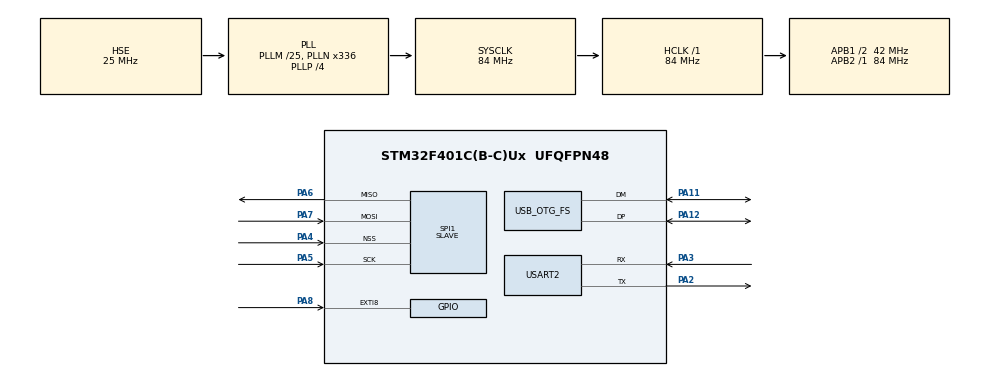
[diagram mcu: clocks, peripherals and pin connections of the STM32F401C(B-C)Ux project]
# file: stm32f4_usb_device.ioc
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Dma.Request0=SPI1_RX
Dma.Request1=SPI1_TX
Dma.Request2=USART2_RX
Dma.Request3=USART2_TX
Dma.SPI1_RX.0.Direction=DMA_PERIPH_TO_MEMORY
Dma.SPI1_RX.0.FIFOMode=DMA_FIFOMODE_DISABLE
Dma.SPI1_RX.0.Instance=DMA2_Stream0
Dma.SPI1_RX.0.MemDataAlignment=DMA_MDATAALIGN_BYTE
Dma.SPI1_RX.0.MemInc=DMA_MINC_ENABLE
Dma.SPI1_RX.0.Mode=DMA_NORMAL
Dma.SPI1_RX.0.PeriphDataAlignment=DMA_PDATAALIGN_BYTE
Dma.SPI1_RX.0.PeriphInc=DMA_PINC_DISABLE
Dma.SPI1_RX.0.Priority=DMA_PRIORITY_LOW
Dma.SPI1_TX.1.Direction=DMA_MEMORY_TO_PERIPH
Dma.SPI1_TX.1.FIFOMode=DMA_FIFOMODE_DISABLE
Dma.SPI1_TX.1.Instance=DMA2_Stream3
Dma.SPI1_TX.1.MemDataAlignment=DMA_MDATAALIGN_BYTE
Dma.SPI1_TX.1.MemInc=DMA_MINC_ENABLE
Dma.SPI1_TX.1.Mode=DMA_NORMAL
Dma.SPI1_TX.1.PeriphDataAlignment=DMA_PDATAALIGN_BYTE
Dma.SPI1_TX.1.PeriphInc=DMA_PINC_DISABLE
Dma.SPI1_TX.1.Priority=DMA_PRIORITY_LOW
Dma.USART2_RX.2.Direction=DMA_PERIPH_TO_MEMORY
Dma.USART2_RX.2.FIFOMode=DMA_FIFOMODE_DISABLE
Dma.USART2_RX.2.Instance=DMA1_Stream5
Dma.USART2_RX.2.MemDataAlignment=DMA_MDATAALIGN_BYTE
Dma.USART2_RX.2.MemInc=DMA_MINC_ENABLE
Dma.USART2_RX.2.Mode=DMA_NORMAL
Dma.USART2_RX.2.PeriphDataAlignment=DMA_PDATAALIGN_BYTE
Dma.USART2_RX.2.PeriphInc=DMA_PINC_DISABLE
Dma.USART2_RX.2.Priority=DMA_PRIORITY_LOW
Dma.USART2_TX.3.Direction=DMA_MEMORY_TO_PERIPH
Dma.USART2_TX.3.FIFOMode=DMA_FIFOMODE_DISABLE
Dma.USART2_TX.3.Instance=DMA1_Stream6
Dma.USART2_TX.3.MemDataAlignment=DMA_MDATAALIGN_BYTE
Dma.USART2_TX.3.MemInc=DMA_MINC_ENABLE
Dma.USART2_TX.3.Mode=DMA_NORMAL
Dma.USART2_TX.3.PeriphDataAlignment=DMA_PDATAALIGN_BYTE
Dma.USART2_TX.3.PeriphInc=DMA_PINC_DISABLE
Dma.USART2_TX.3.Priority=DMA_PRIORITY_LOW
Mcu.Family=STM32F4
Mcu.Name=STM32F401C(B-C)Ux
Mcu.Package=UFQFPN48
NVIC.DMA1_Stream5_IRQn=true\:0\:0\:false\:false\:true\:false\:true
NVIC.DMA1_Stream6_IRQn=true\:0\:0\:false\:false\:true\:false\:true
NVIC.DMA2_Stream0_IRQn=true\:0\:0\:false\:false\:true\:false\:true
NVIC.DMA2_Stream3_IRQn=true\:0\:0\:false\:false\:true\:false\:true
NVIC.EXTI9_5_IRQn=true\:0\:0\:false\:false\:true\:true\:true
NVIC.OTG_FS_IRQn=true\:0\:0\:false\:false\:true\:true\:true
NVIC.PriorityGroup=NVIC_PRIORITYGROUP_4
NVIC.SPI1_IRQn=true\:0\:0\:false\:false\:true\:true\:true
NVIC.TIM1_BRK_TIM9_IRQn=true\:0\:0\:false\:false\:true\:true\:true
NVIC.TIM1_TRG_COM_TIM11_IRQn=true\:0\:0\:false\:false\:true\:true\:true
NVIC.TIM1_UP_TIM10_IRQn=true\:0\:0\:false\:false\:true\:true\:true
NVIC.USART2_IRQn=true\:0\:0\:false\:false\:true\:true\:true
PA11.Mode=Device_Only
PA11.Signal=USB_OTG_FS_DM
PA12.Mode=Device_Only
PA12.Signal=USB_OTG_FS_DP
PA13.Mode=Serial_Wire
PA13.Signal=SYS_JTMS-SWDIO
PA14.Mode=Serial_Wire
PA14.Signal=SYS_JTCK-SWCLK
PA2.Mode=Asynchronous
PA2.Signal=USART2_TX
PA3.Mode=Asynchronous
PA3.Signal=USART2_RX
PA4.Mode=NSS_Signal_Hard_Input
PA4.Signal=SPI1_NSS
PA5.Mode=Full_Duplex_Slave
PA5.Signal=SPI1_SCK
PA6.Mode=Full_Duplex_Slave
PA6.Signal=SPI1_MISO
PA7.Mode=Full_Duplex_Slave
PA7.Signal=SPI1_MOSI
PA8.Signal=GPXTI8
PH0\ -\ OSC_IN.Mode=HSE-External-Oscillator
PH0\ -\ OSC_IN.Signal=RCC_OSC_IN
PH1\ -\ OSC_OUT.Mode=HSE-External-Oscillator
PH1\ -\ OSC_OUT.Signal=RCC_OSC_OUT
ProjectManager.HeapSize=0x200
ProjectManager.StackSize=0x400
ProjectManager.TargetToolchain=STM32CubeIDE
RCC.48MHZClocksFreq_Value=48000000
RCC.AHBFreq_Value=84000000
RCC.APB1CLKDivider=RCC_HCLK_DIV2
RCC.APB1Freq_Value=42000000
RCC.APB1TimFreq_Value=84000000
RCC.APB2Freq_Value=84000000
RCC.APB2TimFreq_Value=84000000
RCC.CortexFreq_Value=84000000
RCC.HCLKFreq_Value=84000000
RCC.HSE_VALUE=25000000
RCC.HSI_VALUE=16000000
RCC.LSE_VALUE=32768
RCC.PLLM=25
RCC.PLLN=336
RCC.PLLP=RCC_PLLP_DIV4
RCC.PLLQ=7
RCC.SYSCLKFreq_VALUE=84000000
RCC.SYSCLKSource=RCC_SYSCLKSOURCE_PLLCLK
RCC.VCOOutputFreq_Value=336000000
SPI1.Direction=SPI_DIRECTION_2LINES
SPI1.Mode=SPI_MODE_SLAVE
SPI1.VirtualNSS=VM_NSSHARD
SPI1.VirtualType=VM_SLAVE
TIM10.Prescaler=8400
TIM11.AutoReloadPreload=TIM_AUTORELOAD_PRELOAD_ENABLE
TIM11.Period=10
TIM11.Prescaler=8400
TIM5.Prescaler=8400
TIM9.Prescaler=8400
USART2.VirtualMode=VM_ASYNC
USB_DEVICE.CLASS_NAME_FS=HID
USB_DEVICE.VirtualMode=Hid
USB_DEVICE.VirtualModeFS=Hid_FS
USB_OTG_FS.VirtualMode=Device_Only
VP_TIM10_VS_ClockSourceINT.Mode=Enable_Timer
VP_TIM11_VS_ClockSourceINT.Mode=Enable_Timer
VP_TIM5_VS_ClockSourceINT.Mode=Internal
VP_TIM9_VS_ClockSourceINT.Mode=Internal
VP_USB_DEVICE_VS_USB_DEVICE_HID_FS.Mode=HID_FS
board=custom

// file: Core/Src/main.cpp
/* USER CODE BEGIN Header */
/**
  ******************************************************************************
  * @file           : main.c
  * @brief          : Main program body
  ******************************************************************************
  * @attention
  *
  * <h2><center>&copy; Copyright (c) 2020 STMicroelectronics.
  * All rights reserved.</center></h2>
  *
  * This software component is licensed by ST under BSD 3-Clause license,
  * the "License"; You may not use this file except in compliance with the
  * License. You may obtain a copy of the License at:
  *                        opensource.org/licenses/BSD-3-Clause
  *
  ******************************************************************************
  */
/* USER CODE END Header */

#include <cstdio>

#include "main.h"
#include "usb_device.h"
#include "usbd_hid.h"
#include "mouse_event_handler.hpp"
#include "circular_buffers.hpp"
#include "key_value_tree.hpp"
#include "rpc_impl.hpp"
#include "matrix.h"

CRC_HandleTypeDef hcrc;

IWDG_HandleTypeDef hiwdg;

SPI_HandleTypeDef hspi1;
DMA_HandleTypeDef hdma_spi1_rx;
DMA_HandleTypeDef hdma_spi1_tx;

TIM_HandleTypeDef htim5;
TIM_HandleTypeDef htim9;
TIM_HandleTypeDef htim10;
TIM_HandleTypeDef htim11;

UART_HandleTypeDef huart2;
DMA_HandleTypeDef hdma_usart2_rx;
DMA_HandleTypeDef hdma_usart2_tx;

WWDG_HandleTypeDef hwwdg;

/* USER CODE BEGIN PV */

int tim11_count = 0;
int tim10_count = 0;
int tim9_count = 0;
int uart_rx_count = 0;
int usb_event_num = 0;
int mouse_event_num = 0;
int keyboard_event_num = 0;
int gpio_pa8_interrupt_count = 0;

#define UART_RX_BUF_SIZE 128
#define UART_TX_BUF_SIZE 512
#define SPI_RX_BUF_SIZE 17

#define USING_DMA_UART 1
#define USING_CIRCULAR_DMA 1

int spi_rx_count = 0;
int spi_error_count = 0;
int spi_half_rx_count = 0;
const uint16_t keep_alive_period = 50'000;
uint32_t uart_rx_dma_remaining_bytes = 0;

#pragma pack(1)
typedef struct
{
	int16_t dx;
	int16_t dy;
	int8_t dz;
	uint32_t buttons;
}
SPI_MMO_Mouse_State_TypeDef;

SPI_MMO_Mouse_State_TypeDef* spi_mouse_state_rx;

uint8_t rx_buf_read_pos = 0;
uint8_t rx_buf[UART_RX_BUF_SIZE];

uint8_t spi_rx_buf[] = "Test Test Test Test Test ";
UART_Tx_CircularBuffer uart2_tx_buf;

extern void test_config(uint8_t test_index, void (*traversal_func)(const uint32_t key, const uint8_t, const uint8_t* data));
/* USER CODE END PV */

void SystemClock_Config(void);
static void MX_GPIO_Init(void);
static void MX_DMA_Init(void);
static void MX_SPI1_Init(void);
static void MX_TIM9_Init(void);
static void MX_TIM5_Init(void);
static void MX_TIM10_Init(void);
static void MX_TIM11_Init(void);
static void MX_USART2_UART_Init(void);
static void MX_CRC_Init(void);
static void MX_IWDG_Init(void);
static void MX_WWDG_Init(void);

/* USER CODE BEGIN 0 */

//extern "C" uint8_t PrintHexBuf(uint8_t *buff, uint8_t len);
uint8_t PrintHexBuf(uint8_t *buff, uint8_t len){
	for(uint8_t i = 0; i<len; i++){
		printf("%02X ",buff[i]);
		if ((i+1)%8 == 0){
			printf("\r\n");
		}
	}
	printf("\r\n");
	return 0;
}

void start_keypress_timer(){
	htim5.Instance->CNT = 0;
	HAL_TIM_Base_Start_IT(&htim5);
}

void stop_keypress_timer(){
	HAL_TIM_Base_Stop_IT(&htim5);
}

uint32_t read_keypress_time_ms(){
	uint32_t cnt = __HAL_TIM_GetCounter(&htim5);
	return cnt/10;
}

extern "C" uint32_t timer_read32();
uint32_t timer_read32(){
	return  __HAL_TIM_GetCounter(&htim5);
}

extern "C" void _delay_us(uint16_t us);
void _delay_us(uint16_t us) // microseconds
{
    uint16_t startTick  = __HAL_TIM_GetCounter(&htim11);
	uint16_t targetTick = startTick + us;

    // Must check if target tick is out of bounds and overflowed
    if (targetTick > startTick) {
        // Not overflowed
        while (__HAL_TIM_GetCounter(&htim11) < targetTick);
    } else {
        // Overflowed
        while (__HAL_TIM_GetCounter(&htim11) > startTick || __HAL_TIM_GetCounter(&htim11) < targetTick);
    }
}

extern "C" uint32_t timer_elapsed32(uint32_t initial_time);
uint32_t timer_elapsed32(uint32_t initial_time){
	uint32_t cnt = __HAL_TIM_GetCounter(&htim5);
	if (initial_time <= cnt){
		return (cnt - initial_time);
	}else{
		return (0xFFFFFFFF - initial_time) + cnt;
	}
}

MouseEventHandler mouse_event_handler(&stop_keypress_timer, &start_keypress_timer, &read_keypress_time_ms);

RPC_Impl* hid_rpc_obj_ptr = NULL;

void spi_rx_complete(SPI_HandleTypeDef *hspi){
	spi_rx_count ++ ;

	printf("SPI RX : %d\r\n",spi_rx_count);
	PrintHexBuf(spi_rx_buf,9);

	spi_mouse_state_rx = (SPI_MMO_Mouse_State_TypeDef*) spi_rx_buf;
	mouse_event_handler.update_state(spi_mouse_state_rx->dx, spi_mouse_state_rx->dy, spi_mouse_state_rx->dz, spi_mouse_state_rx->buttons);

	//This needs to be updated to use mouse_event_handler for it to work properly
	//printf("X:%d Y:%d Z:%d B:0x%x \r\n",accumulated_mouse_del_x,accumulated_mouse_del_y,accumulated_scroll_y,current_primary_button_state);
}

void spi_half_rx_complete(SPI_HandleTypeDef *hspi){
	spi_half_rx_count ++ ;
	printf("SPI Half Received: %d\r\n",spi_rx_count);
}

void spi_rx_error(SPI_HandleTypeDef *hspi){
	spi_error_count ++ ;
	printf("SPI Error: %d\r\n",spi_error_count);
}

void timer11_period_elapsed(TIM_HandleTypeDef *htim){
	tim11_count ++;
	printf("Client alive msg.. %d\r\n",tim11_count);
}

void process_transfer_uart_rx_buf(uint8_t remaining_bytes){
	if ((UART_RX_BUF_SIZE - remaining_bytes)> 0){
		uint8_t bytes_to_transfer = UART_RX_BUF_SIZE - remaining_bytes - rx_buf_read_pos;
		uart2_tx_buf.write_to_queue((char *) &rx_buf[rx_buf_read_pos], bytes_to_transfer);
		rx_buf_read_pos += bytes_to_transfer;
	}
	if(remaining_bytes == 0){
		rx_buf_read_pos = 0;
	}
}

void timer10_period_elapsed(TIM_HandleTypeDef *htim){
	tim10_count ++;

	uart_rx_dma_remaining_bytes = __HAL_DMA_GET_COUNTER(&hdma_usart2_rx);
	process_transfer_uart_rx_buf(uart_rx_dma_remaining_bytes);

	if (HAL_DMA_GetState(&hdma_usart2_tx) == HAL_DMA_STATE_READY){
		auto [ tx_buf, tx_count ] = uart2_tx_buf.longest_possible_send();
		if(tx_count > 0){
			HAL_UART_Transmit_DMA(&huart2,(uint8_t*) tx_buf, tx_count);
		}
	}
}

void timer9_period_elapsed(TIM_HandleTypeDef *htim){
	tim9_count ++;
	//mouse_event_handler.hid_poll_interval_timer_callback();
	matrix_scan();
	matrix_print();
}

void uart_rx_complete(UART_HandleTypeDef *huart){
	process_transfer_uart_rx_buf(0);
	uart_rx_count ++;
}

void uart_tx_complete(UART_HandleTypeDef *huart){
	uart2_tx_buf.last_send_complete();
}

extern "C" int _write(int file, char *ptr, int len);
int _write(int file, char *ptr, int len)
{
	uart2_tx_buf.write_to_queue(ptr, len);
	return len;
}

void Enable_Flash_Interrupts_NVIC(){
	  HAL_NVIC_SetPriority(FLASH_IRQn, 0, 0);
	  HAL_NVIC_EnableIRQ(FLASH_IRQn);
}

void update_key_value_mouse_event_handler(const uint32_t key, const uint8_t size, const uint8_t* data){
	mouse_event_handler.register_config_entry(key, size, data);
}

void HandleHIDOutputMsg(const uint8_t* buf, uint8_t size){
	PrintHexBuf(const_cast<uint8_t*>(buf), size);
	hid_rpc_obj_ptr->Handle_RPC(buf);
}

int main(void)
{

  /* MCU Configuration--------------------------------------------------------*/

  /* Reset of all peripherals, Initializes the Flash interface and the Systick. */
  HAL_Init();

  /* Configure the system clock */
  SystemClock_Config();

  /* Initialize all configured peripherals */
  MX_GPIO_Init();
  MX_DMA_Init();
  MX_SPI1_Init();
  MX_TIM9_Init();
  MX_TIM5_Init();
  MX_TIM10_Init();
  MX_TIM11_Init();
  MX_USART2_UART_Init();
  MX_USB_DEVICE_Init();
  MX_CRC_Init();

  Node_Address flash_config_tree_root_addr = (uint32_t) 0x08004000;
  Flash_Key_Value_Tree r_tree = Flash_Key_Value_Tree((uint32_t)flash_config_tree_root_addr);
  r_tree.reload();

  auto hid_rpc_obj = RPC_Impl({.flash_key_value_tree=&r_tree, .mouse_event_handler=&mouse_event_handler});
  hid_rpc_obj_ptr = &hid_rpc_obj;

  USBD_HID_Register_EP0RX_Callback(HandleHIDOutputMsg);

  //MX_IWDG_Init();
  //MX_WWDG_Init();
  /* USER CODE BEGIN 2 */

  //HAL_TIM_RegisterCallback(&htim11,HAL_TIM_PERIOD_ELAPSED_CB_ID, timer11_period_elapsed);
  HAL_TIM_RegisterCallback(&htim10,HAL_TIM_PERIOD_ELAPSED_CB_ID, timer10_period_elapsed);
  HAL_TIM_RegisterCallback(&htim9,HAL_TIM_PERIOD_ELAPSED_CB_ID, timer9_period_elapsed);

  //HAL_UART_RegisterCallback(&huart2, HAL_UART_TX_COMPLETE_CB_ID, uart_transfer_completed);
  HAL_UART_RegisterCallback(&huart2, HAL_UART_RX_COMPLETE_CB_ID, uart_rx_complete);
  HAL_UART_RegisterCallback(&huart2, HAL_UART_TX_COMPLETE_CB_ID, uart_tx_complete);
  HAL_SPI_RegisterCallback(&hspi1, HAL_SPI_RX_COMPLETE_CB_ID, spi_rx_complete);
  //HAL_SPI_RegisterCallback(&hspi1, HAL_SPI_RX_HALF_COMPLETE_CB_ID, spi_half_rx_complete);
  HAL_SPI_RegisterCallback(&hspi1, HAL_SPI_ERROR_CB_ID, spi_rx_error);

  HAL_TIM_Base_Start_IT(&htim11);
  HAL_TIM_Base_Start_IT(&htim10);
  HAL_TIM_Base_Start_IT(&htim9);

  start_keypress_timer();

  /* USER CODE END 2 */
  HAL_UART_Receive_DMA(&huart2, rx_buf, UART_RX_BUF_SIZE);
  HAL_SPI_Receive_DMA(&hspi1, spi_rx_buf, 9);

  Enable_Flash_Interrupts_NVIC();

  /* Infinite loop */
  /* USER CODE BEGIN WHILE */

  uint32_t pI = 0;
  uint64_t Data = 0x00000000FFFFFFFF;
  uint8_t i = 0;

  r_tree.map_with_key_value_function(update_key_value_mouse_event_handler);

  while (1)
  {
	  /* USER CODE END WHILE */
	  /*
	  HAL_StatusTypeDef a = HAL_FLASH_Unlock();
	  __HAL_FLASH_CLEAR_FLAG(FLASH_FLAG_EOP | FLASH_FLAG_OPERR | FLASH_FLAG_WRPERR | FLASH_FLAG_PGAERR | FLASH_FLAG_PGSERR | FLASH_FLAG_PGPERR);

	  const volatile uint32_t *userConfig = &user_config_sector1;

	  HAL_StatusTypeDef b = HAL_FLASH_Program_IT(FLASH_TYPEPROGRAM_WORD, (uint32_t) userConfig, Data);

	  Data = Data & ~(uint64_t)(0x1<<i);

	  HAL_FLASH_Lock();
	  */

	  //HAL_Delay(1000);
	  //check_on_config();
	  //pI =  USBD_HID_GetPollingInterval(&hUsbDeviceFS);
	  //pI ++;

	  //Why is the flash tree synchronized in the main loop?
	  //1. Why not? The main loop is useless otherwise to this app
	  //2. It provides a convinience place to "watch-dog" this potentially
	  //   dangerous function.
	  //2.a. As its reading the raw flash values and is trying to build a
	  //     (potentially) complicated data structure. It can runaway
	  //	 in its own fantasy land
	  //3. If that happens, the main loop will not be able to kick-the-dog
	  //   which will lead to a "safe-mode" reboot.
	  if(r_tree.needs_syncing()){
		 // r_tree.reload();
	  }

	  i ++;
	  i = i % 32;
  }
}

void SystemClock_Config(void)
{
  RCC_OscInitTypeDef RCC_OscInitStruct = {0};
  RCC_ClkInitTypeDef RCC_ClkInitStruct = {0};

  /** Configure the main internal regulator output voltage
  */
  __HAL_RCC_PWR_CLK_ENABLE();
  __HAL_PWR_VOLTAGESCALING_CONFIG(PWR_REGULATOR_VOLTAGE_SCALE2);
  /** Initializes the CPU, AHB and APB busses clocks
  */
  //Pre WDG
  //RCC_OscInitStruct.OscillatorType = RCC_OSCILLATORTYPE_HSE;

  //Post WDG
  RCC_OscInitStruct.OscillatorType = RCC_OSCILLATORTYPE_LSI|RCC_OSCILLATORTYPE_HSE;
  RCC_OscInitStruct.LSIState = RCC_LSI_ON;

  //Unaffected by WDG
  RCC_OscInitStruct.HSEState = RCC_HSE_ON;
  RCC_OscInitStruct.PLL.PLLState = RCC_PLL_ON;
  RCC_OscInitStruct.PLL.PLLSource = RCC_PLLSOURCE_HSE;
  RCC_OscInitStruct.PLL.PLLM = 25;
  RCC_OscInitStruct.PLL.PLLN = 336;
  RCC_OscInitStruct.PLL.PLLP = RCC_PLLP_DIV4;
  RCC_OscInitStruct.PLL.PLLQ = 7;
  if (HAL_RCC_OscConfig(&RCC_OscInitStruct) != HAL_OK)
  {
    Error_Handler();
  }
  /** Initializes the CPU, AHB and APB busses clocks
  */
  RCC_ClkInitStruct.ClockType = RCC_CLOCKTYPE_HCLK|RCC_CLOCKTYPE_SYSCLK
                              |RCC_CLOCKTYPE_PCLK1|RCC_CLOCKTYPE_PCLK2;
  RCC_ClkInitStruct.SYSCLKSource = RCC_SYSCLKSOURCE_PLLCLK;
  RCC_ClkInitStruct.AHBCLKDivider = RCC_SYSCLK_DIV1;
  RCC_ClkInitStruct.APB1CLKDivider = RCC_HCLK_DIV2;
  RCC_ClkInitStruct.APB2CLKDivider = RCC_HCLK_DIV1;

  if (HAL_RCC_ClockConfig(&RCC_ClkInitStruct, FLASH_LATENCY_2) != HAL_OK)
  {
    Error_Handler();
  }
}

static void MX_CRC_Init(void)
{

  hcrc.Instance = CRC;
  if (HAL_CRC_Init(&hcrc) != HAL_OK)
  {
    Error_Handler();
  }

}

static void MX_IWDG_Init(void)
{

  hiwdg.Instance = IWDG;
  hiwdg.Init.Prescaler = IWDG_PRESCALER_4;
  hiwdg.Init.Reload = 4095;
  if (HAL_IWDG_Init(&hiwdg) != HAL_OK)
  {
    Error_Handler();
  }

}

static void MX_SPI1_Init(void)
{

  /* SPI1 parameter configuration*/
  hspi1.Instance = SPI1;
  hspi1.Init.Mode = SPI_MODE_SLAVE;
  hspi1.Init.Direction = SPI_DIRECTION_2LINES;
  hspi1.Init.DataSize = SPI_DATASIZE_8BIT;
  hspi1.Init.CLKPolarity = SPI_POLARITY_LOW;
  hspi1.Init.CLKPhase = SPI_PHASE_1EDGE;
  hspi1.Init.NSS = SPI_NSS_HARD_INPUT;
  hspi1.Init.FirstBit = SPI_FIRSTBIT_MSB;
  hspi1.Init.TIMode = SPI_TIMODE_DISABLE;
  hspi1.Init.CRCCalculation = SPI_CRCCALCULATION_DISABLE;
  hspi1.Init.CRCPolynomial = 10;
  if (HAL_SPI_Init(&hspi1) != HAL_OK)
  {
    Error_Handler();
  }
}

static void MX_TIM5_Init(void)
{

  TIM_ClockConfigTypeDef sClockSourceConfig = {0};
  TIM_MasterConfigTypeDef sMasterConfig = {0};

  htim5.Instance = TIM5;
  htim5.Init.Prescaler = 21000;
  htim5.Init.CounterMode = TIM_COUNTERMODE_UP;
  htim5.Init.Period = 0xFFFFFFFF;
  htim5.Init.ClockDivision = TIM_CLOCKDIVISION_DIV4;
  htim5.Init.AutoReloadPreload = TIM_AUTORELOAD_PRELOAD_DISABLE;
  if (HAL_TIM_Base_Init(&htim5) != HAL_OK)
  {
    Error_Handler();
  }
  sClockSourceConfig.ClockSource = TIM_CLOCKSOURCE_INTERNAL;
  if (HAL_TIM_ConfigClockSource(&htim5, &sClockSourceConfig) != HAL_OK)
  {
    Error_Handler();
  }
  sMasterConfig.MasterOutputTrigger = TIM_TRGO_RESET;
  sMasterConfig.MasterSlaveMode = TIM_MASTERSLAVEMODE_DISABLE;
  if (HAL_TIMEx_MasterConfigSynchronization(&htim5, &sMasterConfig) != HAL_OK)
  {
    Error_Handler();
  }

}

static void MX_TIM9_Init(void)
{

  TIM_ClockConfigTypeDef sClockSourceConfig = {0};

  htim9.Instance = TIM9;
  htim9.Init.Prescaler = 8400;
  htim9.Init.CounterMode = TIM_COUNTERMODE_UP;
  htim9.Init.Period = 100;
  htim9.Init.ClockDivision = TIM_CLOCKDIVISION_DIV1;
  htim9.Init.AutoReloadPreload = TIM_AUTORELOAD_PRELOAD_DISABLE;
  if (HAL_TIM_Base_Init(&htim9) != HAL_OK)
  {
    Error_Handler();
  }
  sClockSourceConfig.ClockSource = TIM_CLOCKSOURCE_INTERNAL;
  if (HAL_TIM_ConfigClockSource(&htim9, &sClockSourceConfig) != HAL_OK)
  {
    Error_Handler();
  }
}

static void MX_TIM10_Init(void)
{

  htim10.Instance = TIM10;
  htim10.Init.Prescaler = 8400;
  htim10.Init.CounterMode = TIM_COUNTERMODE_UP;
  htim10.Init.Period = 1;
  htim10.Init.ClockDivision = TIM_CLOCKDIVISION_DIV1;
  htim10.Init.AutoReloadPreload = TIM_AUTORELOAD_PRELOAD_DISABLE;
  if (HAL_TIM_Base_Init(&htim10) != HAL_OK)
  {
    Error_Handler();
  }
}

static void MX_TIM11_Init(void)
{

  htim11.Instance = TIM11;
  htim11.Init.Prescaler = 84;
  htim11.Init.CounterMode = TIM_COUNTERMODE_UP;
  htim11.Init.Period = 0xFFFFFFFF;
  htim11.Init.ClockDivision = TIM_CLOCKDIVISION_DIV1;
  htim11.Init.AutoReloadPreload = TIM_AUTORELOAD_PRELOAD_ENABLE;
  if (HAL_TIM_Base_Init(&htim11) != HAL_OK)
  {
    Error_Handler();
  }
}

static void MX_USART2_UART_Init(void)
{

  huart2.Instance = USART2;
  huart2.Init.BaudRate = 1000000;
  huart2.Init.WordLength = UART_WORDLENGTH_8B;
  huart2.Init.StopBits = UART_STOPBITS_1;
  huart2.Init.Parity = UART_PARITY_NONE;
  huart2.Init.Mode = UART_MODE_TX_RX;
  huart2.Init.HwFlowCtl = UART_HWCONTROL_NONE;
  huart2.Init.OverSampling = UART_OVERSAMPLING_16;
  if (HAL_UART_Init(&huart2) != HAL_OK)
  {
    Error_Handler();
  }

}

static void MX_WWDG_Init(void)
{

  hwwdg.Instance = WWDG;
  hwwdg.Init.Prescaler = WWDG_PRESCALER_1;
  hwwdg.Init.Window = 64;
  hwwdg.Init.Counter = 64;
  hwwdg.Init.EWIMode = WWDG_EWI_DISABLE;
  if (HAL_WWDG_Init(&hwwdg) != HAL_OK)
  {
    Error_Handler();
  }

}

static void MX_DMA_Init(void)
{

  /* DMA controller clock enable */
  __HAL_RCC_DMA2_CLK_ENABLE();
  __HAL_RCC_DMA1_CLK_ENABLE();

  /* DMA interrupt init */
  /* DMA1_Stream5_IRQn interrupt configuration */
  HAL_NVIC_SetPriority(DMA1_Stream5_IRQn, 0, 0);
  HAL_NVIC_EnableIRQ(DMA1_Stream5_IRQn);
  /* DMA1_Stream6_IRQn interrupt configuration */
  HAL_NVIC_SetPriority(DMA1_Stream6_IRQn, 0, 0);
  HAL_NVIC_EnableIRQ(DMA1_Stream6_IRQn);
  /* DMA2_Stream0_IRQn interrupt configuration */
  HAL_NVIC_SetPriority(DMA2_Stream0_IRQn, 0, 0);
  HAL_NVIC_EnableIRQ(DMA2_Stream0_IRQn);
  /* DMA2_Stream3_IRQn interrupt configuration */
  HAL_NVIC_SetPriority(DMA2_Stream3_IRQn, 0, 0);
  HAL_NVIC_EnableIRQ(DMA2_Stream3_IRQn);

}

static void MX_GPIO_Init(void)
{
	  GPIO_InitTypeDef GPIO_InitStruct = {0};

	  /* GPIO Ports Clock Enable */
	  __HAL_RCC_GPIOC_CLK_ENABLE();
	  __HAL_RCC_GPIOA_CLK_ENABLE();
	  __HAL_RCC_GPIOB_CLK_ENABLE();

	  /*Configure GPIO pin Output Level */
	  HAL_GPIO_WritePin(GPIOB, GPIO_PIN_12|GPIO_PIN_13|GPIO_PIN_14|GPIO_PIN_15
	                          |GPIO_PIN_3|GPIO_PIN_4|GPIO_PIN_5|GPIO_PIN_6
	                          |GPIO_PIN_7|GPIO_PIN_8|GPIO_PIN_9, GPIO_PIN_RESET);

	  /*Configure GPIO pins : PC13 PC14 PC15 */
	  GPIO_InitStruct.Pin = GPIO_PIN_13|GPIO_PIN_14|GPIO_PIN_15;
	  GPIO_InitStruct.Mode = GPIO_MODE_OUTPUT_PP;
	  GPIO_InitStruct.Pull = GPIO_NOPULL;
	  GPIO_InitStruct.Speed = GPIO_SPEED_FREQ_LOW;
	  HAL_GPIO_Init(GPIOC, &GPIO_InitStruct);

	  /*Configure GPIO pins : PB2 PB10 */
	  GPIO_InitStruct.Pin = GPIO_PIN_2|GPIO_PIN_10;
	  GPIO_InitStruct.Mode = GPIO_MODE_OUTPUT_PP;
	  GPIO_InitStruct.Pull = GPIO_NOPULL;
	  GPIO_InitStruct.Speed = GPIO_SPEED_FREQ_LOW;
	  HAL_GPIO_Init(GPIOB, &GPIO_InitStruct);

	  /*Configure GPIO pins : PB12 PB13 PB14 PB15
	                           PB3 PB4 PB5 PB6
	                           PB7 PB8 PB9 */
	  GPIO_InitStruct.Pin = GPIO_PIN_12|GPIO_PIN_13|GPIO_PIN_14|GPIO_PIN_15
	                          |GPIO_PIN_3|GPIO_PIN_4|GPIO_PIN_5|GPIO_PIN_6
	                          |GPIO_PIN_7|GPIO_PIN_8|GPIO_PIN_9;
	  GPIO_InitStruct.Mode = GPIO_MODE_INPUT;
	  GPIO_InitStruct.Pull = GPIO_PULLUP;
	  HAL_GPIO_Init(GPIOB, &GPIO_InitStruct);

}

void Error_Handler(void)
{
}

/************************ (C) COPYRIGHT STMicroelectronics *****END OF FILE****/
